VERSION 5.7 ;
  NOWIREEXTENSIONATPIN ON ;
  DIVIDERCHAR "/" ;
  BUSBITCHARS "[]" ;
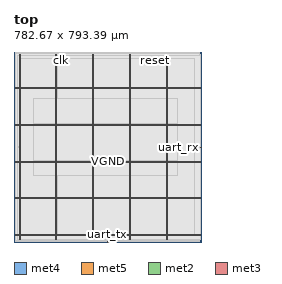
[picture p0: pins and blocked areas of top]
MACRO top
  CLASS BLOCK ;
  FOREIGN top ;
  ORIGIN 0.000 0.000 ;
  SIZE 782.670 BY 793.390 ;
  PIN VGND
    DIRECTION INOUT ;
    USE GROUND ;
    PORT
      LAYER met4 ;
        RECT 24.340 10.640 25.940 780.880 ;
    END
    PORT
      LAYER met4 ;
        RECT 177.940 10.640 179.540 780.880 ;
    END
    PORT
      LAYER met4 ;
        RECT 331.540 10.640 333.140 780.880 ;
    END
    PORT
      LAYER met4 ;
        RECT 485.140 10.640 486.740 780.880 ;
    END
    PORT
      LAYER met4 ;
        RECT 638.740 10.640 640.340 780.880 ;
    END
    PORT
      LAYER met5 ;
        RECT 5.280 30.030 777.180 31.630 ;
    END
    PORT
      LAYER met5 ;
        RECT 5.280 183.210 777.180 184.810 ;
    END
    PORT
      LAYER met5 ;
        RECT 5.280 336.390 777.180 337.990 ;
    END
    PORT
      LAYER met5 ;
        RECT 5.280 489.570 777.180 491.170 ;
    END
    PORT
      LAYER met5 ;
        RECT 5.280 642.750 777.180 644.350 ;
    END
  END VGND
  PIN VPWR
    DIRECTION INOUT ;
    USE POWER ;
    PORT
      LAYER met4 ;
        RECT 21.040 10.640 22.640 780.880 ;
    END
    PORT
      LAYER met4 ;
        RECT 174.640 10.640 176.240 780.880 ;
    END
    PORT
      LAYER met4 ;
        RECT 328.240 10.640 329.840 780.880 ;
    END
    PORT
      LAYER met4 ;
        RECT 481.840 10.640 483.440 780.880 ;
    END
    PORT
      LAYER met4 ;
        RECT 635.440 10.640 637.040 780.880 ;
    END
    PORT
      LAYER met5 ;
        RECT 5.280 26.730 777.180 28.330 ;
    END
    PORT
      LAYER met5 ;
        RECT 5.280 179.910 777.180 181.510 ;
    END
    PORT
      LAYER met5 ;
        RECT 5.280 333.090 777.180 334.690 ;
    END
    PORT
      LAYER met5 ;
        RECT 5.280 486.270 777.180 487.870 ;
    END
    PORT
      LAYER met5 ;
        RECT 5.280 639.450 777.180 641.050 ;
    END
  END VPWR
  PIN clk
    DIRECTION INPUT ;
    USE SIGNAL ;
    ANTENNAGATEAREA 1.286700 ;
    ANTENNADIFFAREA 0.434700 ;
    PORT
      LAYER met2 ;
        RECT 195.590 789.390 195.870 793.390 ;
    END
  END clk
  PIN reset
    DIRECTION INPUT ;
    USE SIGNAL ;
    ANTENNAGATEAREA 0.126000 ;
    PORT
      LAYER met2 ;
        RECT 586.590 789.390 586.870 793.390 ;
    END
  END reset
  PIN uart_rx
    DIRECTION INPUT ;
    USE SIGNAL ;
    ANTENNAGATEAREA 0.126000 ;
    PORT
      LAYER met3 ;
        RECT 778.670 395.800 782.670 396.400 ;
    END
  END uart_rx
  PIN uart_tx
    DIRECTION OUTPUT TRISTATE ;
    USE SIGNAL ;
    ANTENNADIFFAREA 0.340600 ;
    PORT
      LAYER met2 ;
        RECT 391.090 0.000 391.370 4.000 ;
    END
  END uart_tx
  OBS
      LAYER li1 ;
        RECT 5.520 10.795 776.940 780.725 ;
      LAYER met1 ;
        RECT 5.520 10.640 777.240 780.880 ;
      LAYER met2 ;
        RECT 7.000 789.110 195.310 789.390 ;
        RECT 196.150 789.110 586.310 789.390 ;
        RECT 587.150 789.110 775.930 789.390 ;
        RECT 7.000 4.280 775.930 789.110 ;
        RECT 7.000 4.000 390.810 4.280 ;
        RECT 391.650 4.000 775.930 4.280 ;
      LAYER met3 ;
        RECT 13.405 396.800 778.670 780.805 ;
        RECT 13.405 395.400 778.270 396.800 ;
        RECT 13.405 10.715 778.670 395.400 ;
      LAYER met4 ;
        RECT 27.895 27.375 174.240 766.185 ;
        RECT 176.640 27.375 177.540 766.185 ;
        RECT 179.940 27.375 327.840 766.185 ;
        RECT 330.240 27.375 331.140 766.185 ;
        RECT 333.540 27.375 481.440 766.185 ;
        RECT 483.840 27.375 484.740 766.185 ;
        RECT 487.140 27.375 635.040 766.185 ;
        RECT 637.440 27.375 638.340 766.185 ;
        RECT 640.740 27.375 752.265 766.185 ;
      LAYER met5 ;
        RECT 81.540 492.770 682.060 600.900 ;
        RECT 81.540 339.590 682.060 484.670 ;
        RECT 81.540 279.700 682.060 331.490 ;
  END
END top
END LIBRARY

